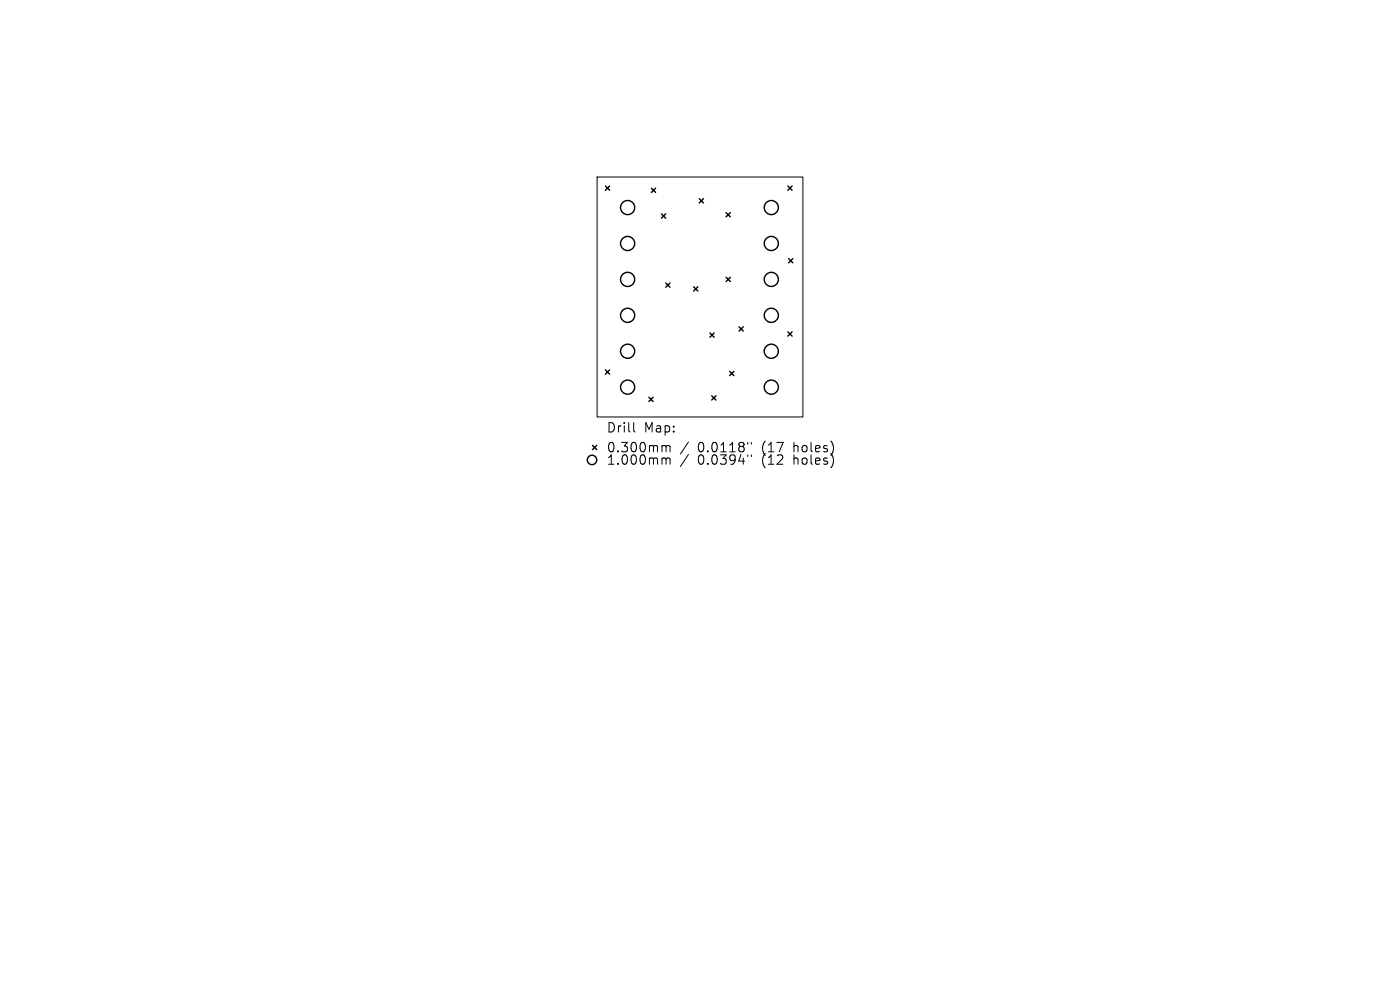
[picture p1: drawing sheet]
<svg xmlns="http://www.w3.org/2000/svg" width="297mm" height="210mm" viewBox="0 0 297 210" stroke-linecap="round" stroke-linejoin="round" font-family="sans-serif">
<defs><g id="words">
<g font-size="2.8">
<text x="128.6" y="92">Drill</text>
<text x="136.6" y="92">Map:</text>
<text x="128.6" y="96.2">0.300mm</text>
<text x="128.6" y="98.9">1.000mm</text>
<text x="148" y="96.2">0.0118&quot;</text>
<text x="148" y="98.9">0.0394&quot;</text>
<text x="161.8" y="96.2">(17</text>
<text x="161.8" y="98.9">(12</text>
<text x="168.6" y="96.2">holes)</text>
<text x="168.6" y="98.9">holes)</text>
</g>
</g></defs>
<g fill="none" stroke="#000" stroke-width=".21">
<path d="M126.7 37.6h43.6v50.9h-43.6zM134.4 89.6v1.8l.3 .2M140.7 94.5l.5 .1 .1 .2M140.7 97.1h.3l.3 .3M141.3 94.8l.3-.3 .5 .1 .1 1.2M141.3 94.8v1M141.3 97.4v1.1M141.3 97.4l.3-.3 .5 .1 .1 1.3M146.1 93.7l-1.8 2.6M146.1 96.4l-1.8 2.6M158.6 93.8v.4M158.6 96.5v.4"/>
<path d="M159.4 93.8v.4M159.4 96.5v.4"/>
</g>
<g fill="none" stroke="#000" stroke-width=".3">
<path d="M128.4 39.5l.9 .9M129.3 39.5l-.9 .9M138.2 39.9l.9 .9M139.1 39.9l-.9 .9M167.1 39.5l.9 .9M168 39.5l-.9 .9M140.3 45.4l.9 .9M141.2 45.4l-.9 .9M148.3 42.1l.9 .9M149.2 42.1l-.9 .9M154 45.1l.9 .9M154 58.8l.9 .9"/>
<path d="M154.9 45.1l-.9 .9M154.9 58.8l-.9 .9M167.3 54.9l.9 .9M168.2 54.9l-.9 .9M128.4 78.5l.9 .9M129.3 78.5l-.9 .9M141.2 60l.9 .9M142.1 60l-.9 .9M147.1 60.8l.9 .9M148 60.8l-.9 .9M150.6 70.6l.9 .9M151.5 70.6l-.9 .9"/>
<path d="M154.8 78.8l.9 .9M155.7 78.8l-.9 .9M156.8 69.3l.9 .9M157.7 69.3l-.9 .9M167.1 70.4l.9 .9M168 70.4l-.9 .9M125.7 94.5l.9 .9M126.6 94.5l-.9 .9M137.6 84.3l.9 .9M138.5 84.3l-.9 .9M151 84l.9 .9M151.9 84l-.9 .9"/>
<circle cx="133.1" cy="44" r="1.5"/>
<circle cx="133.1" cy="59.3" r="1.5"/>
<circle cx="133.1" cy="51.6" r="1.5"/>
<circle cx="163.6" cy="44" r="1.5"/>
<circle cx="163.6" cy="59.3" r="1.5"/>
<circle cx="163.6" cy="51.6" r="1.5"/>
<circle cx="133.1" cy="66.9" r="1.5"/>
<circle cx="133.1" cy="74.5" r="1.5"/>
<circle cx="163.6" cy="74.5" r="1.5"/>
<circle cx="163.6" cy="66.9" r="1.5"/>
<circle cx="125.6" cy="97.6" r="1"/>
<circle cx="133.1" cy="82.1" r="1.5"/>
<circle cx="163.6" cy="82.1" r="1.5"/>
</g>
<use href="#words"/>
</svg>
